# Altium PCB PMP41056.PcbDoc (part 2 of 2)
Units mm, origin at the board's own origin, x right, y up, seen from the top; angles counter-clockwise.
Board outline 20.9 x 34.9 mm, 4 copper layers (Top Layer, Layer 1, Layer 2, Bottom Layer), stack 1.926 mm thick; 24 components, 34 nets, 167 pads, 756 vias.

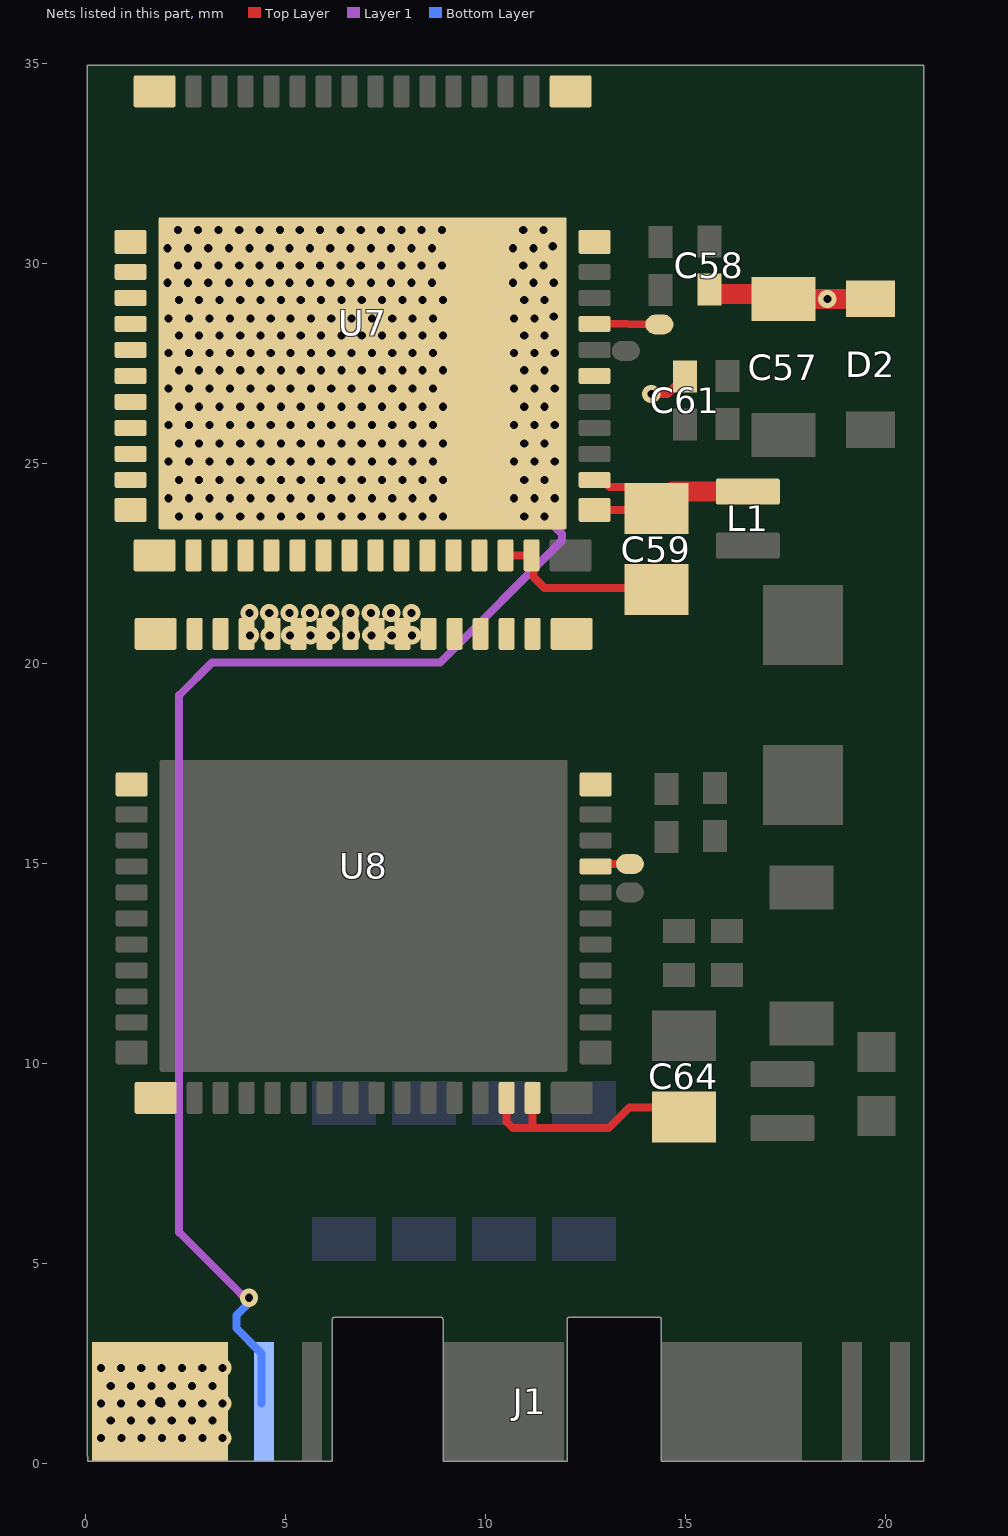
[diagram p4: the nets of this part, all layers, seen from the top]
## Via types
v1: diameter 0.457, hole 0.203, Top Layer to Bottom Layer, tented both sides, 753 vias
v2: diameter 0.5, hole 0.25, Top Layer to Bottom Layer, tented both sides, 3 vias

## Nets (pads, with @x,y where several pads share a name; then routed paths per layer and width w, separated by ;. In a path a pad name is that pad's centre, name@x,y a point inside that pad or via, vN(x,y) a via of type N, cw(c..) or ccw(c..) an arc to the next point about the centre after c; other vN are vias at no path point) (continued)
SW: C57.2 C58.2 C59.2 C61.1 D2.2 J1.8 J1.SW L1.1 U7.18 U7.19 U7.20 U7.21 U7.22 U7.23 U7.24 U7.25 U7.26 U7.27 U7.29 U7.30 U7.31 U7.32 U7.33 U7.34 U7.35 U7.36 U7.37 U7.38 U7.39 U7.40 U7.44 U7.45 U7.49 U7.55 U8.2 U8.3 U8.4 U8.5 U8.6 U8.7 U8.8 U8.9 U8.10 U8.11 U8.12 U8.13 U8.14 U8.15 | length 42.6
  Top Layer w0.2: U7.44@12.73,23.837 C59.2@14.646,23.837 ; U7.45@12.73,24.587 12.93,24.587 13.106,24.411 13.739,24.411 C59.2@14.274,23.876 C59.2@14.695,24.297 ; v1(14.148,26.734) 14.553,26.734 C61.1@14.994,27.175 ; L1.1@16.56,24.297 16.624,24.297 L1.1@16.799,24.472
  Top Layer w0.5: C59.2@14.695,24.297 L1.1@16.56,24.297 ; C58.2@15.599,29.351 15.599,29.279 15.649,29.229 17.327,29.229 C57.2@17.449,29.108 17.451,29.11 v1(18.548,29.11) 19.626,29.11 D2.2@19.628,29.112
  Layer 1 w0.2: v1(4.089,4.14) 4.087,4.14 4.051,4.104 3.928,4.227 3.895,4.227 2.345,5.777 2.345,19.205 3.165,20.026 8.87,20.026 11.916,23.071 11.916,23.237 v1(11.48,23.673)
  Bottom Layer w0.2: v1(4.089,4.14) 4.089,4.077 4.12,4.047 3.775,3.702 3.775,3.38 4.405,2.75 J1.8@4.405,1.5
  other v1: 0.394,0.636 0.899,0.636 1.405,0.636 1.911,0.636 2.417,0.636 2.923,0.636 3.429,0.636 0.635,1.068 1.143,1.068 1.651,1.068 2.159,1.068 2.667,1.068 3.175,1.068 0.394,1.5 0.889,1.5 1.397,1.5 1.905,1.5 2.413,1.5 2.921,1.5 3.429,1.5 0.635,1.932 1.143,1.932 1.651,1.932 2.159,1.932 2.667,1.932 3.175,1.932 0.394,2.389 0.889,2.389 1.397,2.389 1.905,2.389 2.413,2.389 2.921,2.389 3.429,2.389 4.114,20.701 4.609,20.701 5.117,20.701 5.625,20.701 6.133,20.701 6.641,20.701 7.149,20.701 7.657,20.701 8.165,20.701 4.101,21.262 4.596,21.262 5.104,21.262 5.612,21.262 6.12,21.262 6.628,21.262 7.136,21.262 7.644,21.262 8.152,21.262 2.336,23.673 2.844,23.673 3.352,23.673 3.873,23.673 4.381,23.673 4.889,23.673 5.384,23.673 5.892,23.673 6.4,23.673 6.908,23.673 7.416,23.673 7.924,23.673 8.432,23.673 8.94,23.673 10.972,23.673 2.082,24.13 2.59,24.13 3.098,24.13 3.619,24.13 4.127,24.13 4.635,24.13 5.13,24.13 5.638,24.13 6.146,24.13 6.654,24.13 7.162,24.13 7.67,24.13 8.178,24.13 8.686,24.13 10.718,24.13 11.226,24.13 11.734,24.13 2.336,24.587 2.844,24.587 3.352,24.587 3.873,24.587 4.381,24.587 4.889,24.587 5.384,24.587 5.892,24.587 6.4,24.587 6.908,24.587 7.416,24.587 7.924,24.587 8.432,24.587 8.94,24.587 10.972,24.587 11.48,24.587 2.082,25.044 2.59,25.044 3.098,25.044 3.619,25.044 4.127,25.044 4.635,25.044 5.13,25.044 5.638,25.044 6.146,25.044 6.654,25.044 7.162,25.044 7.67,25.044 8.178,25.044 8.686,25.044 10.718,25.044 11.226,25.044 11.734,25.044 2.336,25.502 2.844,25.502 3.352,25.502 3.873,25.502 4.381,25.502 4.889,25.502 5.384,25.502 5.892,25.502 6.4,25.502 6.908,25.502 7.416,25.502 7.924,25.502 8.432,25.502 8.94,25.502 10.972,25.502 11.48,25.502 2.082,25.959 2.59,25.959 3.098,25.959 3.619,25.959 4.127,25.959 4.635,25.959 5.13,25.959 5.638,25.959 6.146,25.959 6.654,25.959 7.162,25.959 7.67,25.959 8.178,25.959 8.686,25.959 10.718,25.959 11.226,25.959 11.734,25.959 2.336,26.416 2.844,26.416 3.352,26.416 3.873,26.416 4.381,26.416 4.889,26.416 5.384,26.416 5.892,26.416 6.4,26.416 6.908,26.416 7.416,26.416 7.924,26.416 8.432,26.416 8.94,26.416 10.972,26.416 11.48,26.416 2.082,26.873 2.59,26.873 3.098,26.873 3.619,26.873 4.127,26.873 4.635,26.873 5.13,26.873 5.638,26.873 6.146,26.873 6.654,26.873 7.162,26.873 7.67,26.873 8.178,26.873 8.686,26.873 10.718,26.873 11.226,26.873 11.734,26.873 2.336,27.33 2.844,27.33 3.352,27.33 3.873,27.33 4.381,27.33 4.889,27.33 5.384,27.33 5.892,27.33 6.4,27.33 6.908,27.33 7.416,27.33 7.924,27.33 8.432,27.33 8.94,27.33 10.972,27.33 11.48,27.33 2.082,27.762 2.59,27.762 3.098,27.762 3.619,27.762 4.127,27.762 4.635,27.762 5.13,27.762 5.638,27.762 6.146,27.762 6.654,27.762 7.162,27.762 7.67,27.762 8.178,27.762 8.686,27.762 10.718,27.762 11.226,27.762 11.734,27.762 2.336,28.194 2.844,28.194 3.352,28.194 3.873,28.194 4.381,28.194 4.889,28.194 5.384,28.194 5.892,28.194 6.4,28.194 6.908,28.194 7.416,28.194 7.924,28.194 8.432,28.194 8.94,28.194 10.972,28.194 11.48,28.194 2.082,28.626 2.59,28.626 3.098,28.626 3.619,28.626 4.127,28.626 4.635,28.626 5.13,28.626 5.638,28.626 6.146,28.626 6.654,28.626 7.162,28.626 7.67,28.626 8.178,28.626 8.686,28.626 10.718,28.626 11.226,28.626 11.708,28.677 2.336,29.083 2.844,29.083 3.352,29.083 3.873,29.083 4.381,29.083 4.889,29.083 5.384,29.083 5.892,29.083 6.4,29.083 6.908,29.083 7.416,29.083 7.924,29.083 8.432,29.083 8.94,29.083 10.972,29.083 11.48,29.083 2.056,29.515 2.564,29.515 3.072,29.515 3.593,29.515 4.101,29.515 4.609,29.515 5.104,29.515 5.612,29.515 6.12,29.515 6.628,29.515 7.136,29.515 7.644,29.515 8.152,29.515 8.66,29.515 10.692,29.515 11.2,29.515 11.708,29.515 2.31,29.947 2.818,29.947 3.326,29.947 3.847,29.947 4.355,29.947 4.863,29.947 5.358,29.947 5.866,29.947 6.374,29.947 6.882,29.947 7.39,29.947 7.898,29.947 8.406,29.947 8.914,29.947 10.946,29.947 11.454,29.947 2.056,30.378 2.564,30.378 3.072,30.378 3.593,30.378 4.101,30.378 4.609,30.378 5.104,30.378 5.612,30.378 6.12,30.378 6.628,30.378 7.136,30.378 7.644,30.378 8.152,30.378 8.66,30.378 10.692,30.378 11.2,30.378 11.683,30.429 2.31,30.836 2.818,30.836 3.326,30.836 3.847,30.836 4.355,30.836 4.863,30.836 5.358,30.836 5.866,30.836 6.374,30.836 6.882,30.836 7.39,30.836 7.898,30.836 8.406,30.836 8.914,30.836 10.946,30.836 11.454,30.836
  other v2: 1.864,1.537
TEMP_H: pad.5@14.35,28.473 U7.51 | length 1.6
  Top Layer w0.2: U7.51@12.773,28.487 12.785,28.499 pad.5@14.35,28.473
TEMP_L: pad.5@13.614,14.986 U8.51 | length 0.9
  Top Layer w0.2: U8.51@12.757,14.924 12.819,14.986 pad.5@13.614,14.986
U1NC1: U7.1
U1NC16: U7.16
U1NC17: U7.17
U1NC28: U7.28
U1NC54: U7.54
U2NC1: U8.1
U2NC16: U8.16
U2NC17: U8.17
U2NC28: U8.28
U2NC54: U8.54
VNEG_H: C59.1 U7.41 U7.42 | length 5.1
  Top Layer w0.2: U7.41@10.505,22.702 U7.42@11.155,22.702 11.205,22.652 11.205,22.157 11.476,21.886 C59.1@14.819,21.886 ; C59.1@14.565,21.886 C59.1@14.646,21.805
VNEG_L: C64.1 U8.41 U8.42 | length 6.1
  Top Layer w0.2: U8.41@10.532,9.139 10.532,8.541 10.692,8.38 11.182,8.38 ; U8.42@11.182,9.139 11.182,8.38 ; C64.1@14.95,8.902 13.6,8.902 13.078,8.38 11.182,8.38

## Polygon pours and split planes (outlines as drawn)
HVBUS on Layer 2 "LAYER_2_HVBUS_P024" (solid, remove dead copper, pour order 24): 1.47,34.925 15.293,34.925 17.195,33.023 17.195,7.747 14.02,4.572 6.514,4.572 5.664,5.422 5.664,7.28 8.127,7.293 9.334,8.5 9.334,30.903 8.106,32.131 2.892,32.131 1.47,33.553
PGND on Layer 2 "LAYER_2_PGND_P043" (solid, remove dead copper, pour order 43): 19.221,0 19.221,6.523 19.221,7.21 18.683,7.747 17.734,7.747 14.509,4.522 14.509,0
SW on Layer 2 "LAYER_2_SW_P025" (solid, remove dead copper, pour order 25): 9.324,31.109 9.324,22.782 8.767,22.225 8.767,20.299 8.66,20.193 4.863,20.193 3.545,18.875 3.545,4.053 4.005,3.594 4.005,0 0.05,0 0.05,30.076 1.13,31.156 9.276,31.156
PGND on Layer 2 "LAYER_2_PGND_P028" (solid, remove dead copper, pour order 28): 12.187,17.719 12.216,13.513 10.359,13.513 10.359,17.535 10.543,17.719
SW on Layer 2 "LAYER_2_SW_P039" (solid, remove dead copper, pour order 39): 12.162,23.444 12.162,30.707 11.55,31.318 10.85,31.318 10.464,30.932 10.464,23.779 10.76,23.483
PGND on Layer 2 "LAYER_2_PGND_P027" (solid, remove dead copper, pour order 27): 12.242,9.797 12.214,13.772 10.359,13.772 10.359,10.081 10.643,9.797
PGND on Layer 2 "LAYER_2_PGND_P026" (solid, remove dead copper, pour order 26): 9.268,17.642 3.897,17.642 3.873,17.618 3.873,8.289 8.936,8.289 9.249,8.602
HVBUS on Layer 1 "LAYER_1_HVBUS_P034" (solid, remove dead copper, pour order 34): 12.347,0.204 12.347,2.569 13.512,3.734 13.512,6.35 5.664,6.35 5.664,5.422 6.514,4.572 6.896,4.572 8.432,3.036 8.432,0.219 8.447,0.204
PGND on Layer 1 "LAYER_1_PGND_P042" (solid, remove dead copper, pour order 42): 20.812,17.907 10.731,17.907 10.359,17.535 10.359,10.053 10.799,9.613 18.826,9.613 20.812,11.599
SW on Layer 1 "LAYER_1_SW_P030" (solid, remove dead copper, pour order 30): 20.097,23.247 10.311,23.247 10.311,31.397 20.097,31.397
PGND on Layer 1 "Layer 1-PGND" (solid, remove dead copper, pour order 37): 19.376,5.612 19.376,9.086 19.065,9.397 10.687,9.397 10.58,9.441 10.102,9.919 10.058,10.026 10.058,17.907 4.378,17.907 3.926,17.455 3.926,8.515 5.243,7.198 13.966,7.198 14.782,6.382 14.782,0 18.505,0 19.065,0.56 19.065,5.301
SW on Layer 1 "LAYER_1_SW_P029" (solid, remove dead copper, pour order 29): 2.91,20.193 9.956,20.193 9.956,31.397 1.371,31.398 0.204,30.23 0.204,0 4.005,0 4.005,3.881 2.027,5.858 2.027,19.31
HVBUS on Layer 1 "LAYER_1_HVBUS_P040" (solid, remove dead copper, pour order 40): 0.659,32.131 17.195,32.131 17.195,34.925 0.659,35
HVBUS on Bottom Layer "BOTTOM_LAYER_HVBUS_P023" (solid, remove dead copper, pour order 23): 13.504,0 8.556,0 8.556,3.074 5.664,5.966 5.664,6.35 13.504,6.35
PGND on Bottom Layer "Top Layer-PGND" (solid, remove dead copper, pour order 36): 20.655,7.01 19.699,7.01 18.576,5.887 18.576,0.914 18.297,0.635 14.909,0.635 14.782,0.762 14.782,7.198 13.576,8.404 0.638,8.404 0.204,8.838 0.204,17.719 0.392,17.907 10.356,17.907 20.655,17.907
SW on Bottom Layer "BOTTOM_LAYER_SW_P033" (solid, remove dead copper, pour order 33): 0.832,31.318 19.044,31.318 20.097,30.265 20.097,21.862 17.789,19.553 1.113,19.553 0.204,20.463 0.204,30.69
HVBUS on Bottom Layer "BOTTOM_LAYER_HVBUS_P041" (solid, remove dead copper, pour order 41): 0.891,33.147 17.195,33.147 17.195,34.925 0.862,34.925
HVBUS on Top Layer "TOP_LAYER_HVBUS_P038" (solid, remove dead copper, pour order 38): 11.963,0.204 11.963,2.651 13.512,4.199 13.512,5.966 13.128,6.35 5.664,6.35 5.664,5.706 6.798,4.572 8.763,2.607 8.763,0.204
PGND on Top Layer "TOP_LAYER_PGND_P035" (solid, remove dead copper, pour order 35): 12.807,8.315 12.807,17.907 0.392,17.907 0.204,17.719 0.204,8.637 0.526,8.315
SW on Top Layer "TOP_LAYER_SW_P031" (solid, remove dead copper, pour order 31): 12.91,31.398 1.723,31.398 0.59,30.265 0.59,21.914 2.31,20.193 12.91,20.193
HVBUS on Top Layer "TOP_LAYER_HVBUS_P032" (solid, remove dead copper, pour order 32): 2.194,33.147 17.195,33.147 17.195,34.925 2.164,34.925

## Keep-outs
Keep-Out Layer:
  text ".Layer_Name" at 41.348,-59.464 h1.52

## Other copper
Top Layer:
  region net PGND: 18.429,6.401 14.86,6.401 14.86,0.254 18.429,0.254
  text ".Layer_Name" at 41.348,-59.464 h1.52
Bottom Layer:
  text ".Layer_Name" at 41.348,-59.464 h1.52

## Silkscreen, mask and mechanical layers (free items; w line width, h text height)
Top Overlay:
  text ".Layer_Name" at 41.348,-59.464 h1.52
Bottom Overlay:
  text "'.PRJ_Number'.PCB_Rev" at -95.734,-34.38 h2.75
  text ".Layer_Name" at 41.348,-59.464 h1.52
Top Paste:
  text ".Layer_Name" at 41.348,-59.464 h1.52
Bottom Paste:
  region: 8.94,30.988 5.94,30.988 5.94,27.988 8.94,27.988
  region: 5.257,30.988 2.257,30.988 2.257,27.988 5.257,27.988
  region: 8.94,24.257 8.94,27.257 5.94,27.257 5.94,24.257
  region: 5.257,24.257 5.257,27.257 2.257,27.257 2.257,24.257
  region: 8.94,20.749 8.94,23.749 5.94,23.749 5.94,20.749
  region: 5.257,20.749 5.257,23.749 2.257,23.749 2.257,20.749
  region: 13.893,20.749 13.893,23.749 10.893,23.749 10.893,20.749
  region: 17.576,20.749 17.576,23.749 14.576,23.749 14.576,20.749
  region: 13.893,24.257 13.893,27.257 10.893,27.257 10.893,24.257
  region: 17.576,24.257 17.576,27.257 14.576,27.257 14.576,24.257
  region: 13.893,30.988 10.893,30.988 10.893,27.988 13.893,27.988
  region: 17.576,30.988 14.576,30.988 14.576,27.988 17.576,27.988
  rectangle: 1.876,14.224 4.876,17.224
  rectangle: 1.876,10.541 4.876,13.541
  rectangle: 5.384,14.224 8.384,17.224
  rectangle: 5.384,10.541 8.384,13.541
  region: 12.115,14.224 12.115,17.224 9.115,17.224 9.115,14.224
  region: 12.115,10.541 12.115,13.541 9.115,13.541 9.115,10.541
  text ".Layer_Name" at 41.348,-59.464 h1.52
Top Solder:
  text ".Layer_Name" at 41.348,-59.464 h1.52
Bottom Solder:
  region: 18.49,9.891 18.49,17.891 13.081,17.891 13.081,9.891
  region: 12.496,9.919 12.496,17.919 1.496,17.919 1.496,9.919
  region: 18.177,31.385 10.177,31.385 10.177,20.385 18.177,20.385
  region: 9.451,31.318 1.451,31.318 1.451,20.318 9.451,20.318
  text ".Layer_Name" at 41.348,-59.464 h1.52
  text ".Layer_Name" at 41.348,-59.464 h1.52
Drill Guide:
  text ".Layer_Name" at 41.348,-59.464 h1.52
M1 Board Outline:
  lines w0.1: 0,0 0,35 ; 0.005,0.165 0.005,0 6.223,0 6.223,3.6 8.89,3.6 8.89,0 12.09,0 12.09,3.6 14.351,3.6 14.351,0 21.005,0 21.005,35 ; 0,35 ccw(c0,35) 0,35 ; 0,35 21.005,35 ; 21.005,35 ccw(c21.005,35) 21.005,35 ; 21.005,35 21.005,35
  text "hole in PAD" at 23.292,1.168 h1.52 r90
  text ".Layer_Name" at 41.348,-59.464 h1.52
M2 Board Dimensions:
  region: 56.004,-41.468 52.829,-41.468 52.829,-44.643 56.004,-44.643
  region: 52.829,-44.643 43.304,-44.643 43.304,-47.818 52.829,-47.818
  lines w0.178: 30.604,-44.643 56.004,-44.643 ; 36.954,-47.818 36.954,-41.468 ; 43.304,-47.818 43.304,-41.468 ; 49.654,-47.818 49.654,-41.468 ; 52.829,-47.818 52.829,-41.468 ; 30.604,-47.818 56.004,-47.818 56.004,-41.468 30.604,-41.468 30.604,-47.818
  text ".Layer_Name" at 41.348,-59.464 h1.52
M3 3D STEP Top:
  text ".Layer_Name" at 41.348,-59.464 h1.52
M4 3D STEP Bottom:
  text ".Layer_Name" at 41.348,-59.464 h1.52
M5 Assembly Top:
  lines w0.254: -104.257,-61.297 63.383,-61.297 ; -104.257,-56.133 63.434,-56.133 ; -104.257,-50.968 -104.257,-66.462 -2.53,-66.462 63.434,-66.462 63.434,-50.968 -104.245,-50.968 -104.245,-66.462 -64.227,-66.462 ; -41.646,-66.462 -41.646,-50.968 ; -9.464,-56.133 -9.464,-50.968 ; 11.872,-56.133 11.872,-50.968 ; 27.67,-66.627 27.67,-61.475
  text "COMPONENTS MARKED 'DNP' SHOULD NOT BE POPULATED." at -98.987,-45.736 h1.52
  text "ASSEMBLY VARIANT:" at -98.86,-48.682 h1.52
  text ".VariantName" at -72.469,-48.682 h1.52
  text "PCB VIEWED FROM BOTTOM SIDE" at -102.644,-54.325 h1.52
  text "BOARD #:" at -39.741,-54.325 h1.52
  text ".PRJ_Number" at -25.886,-54.325 h1.52
  text "REV:" at -4.435,-54.325 h1.52
  text ".PCB_Rev" at 2.969,-54.325 h1.52
  text "SVN REV:" at 16.85,-54.325 h1.52
  text ".VersionControl_RevNumber" at 29.702,-54.325 h1.52
  text "TID #:" at -39.741,-59.49 h1.52
  text ".TID" at -25.886,-59.49 h1.52
  text "PLOT NAME =" at -102.644,-64.705 h1.52
  text ".plot_File_Name" at -82.185,-64.705 h1.52
  text "GENERATED    :" at -39.69,-64.705 h1.52
  text ".Print_Date" at -17.605,-64.705 h1.52
  text ".Print_Time" at 0.911,-64.705 h1.52
  text "TEXAS INSTRUMENTS" at 33.03,-64.705 h1.52
M6 Assembly Bottom:
  lines w0.254: -104.27,-56.12 63.421,-56.12 ; -104.219,-61.285 63.421,-61.285 ; -68.507,-66.614 -68.507,-61.463 ; -52.708,-56.12 -52.708,-50.955 ; -31.372,-56.12 -31.372,-50.955 ; 0.81,-66.449 0.81,-50.955 ; 23.39,-66.449 63.408,-66.449 63.408,-50.955 -104.27,-50.955 -104.27,-66.449 -38.306,-66.449 63.421,-66.449 63.421,-50.955
  text "COMPONENTS MARKED 'DNP' SHOULD NOT BE POPULATED." at 26.705,-45.748 h1.52
  text ".VariantName" at 0.403,-48.682 h1.52
  text "ASSEMBLY VARIANT:" at 26.718,-48.682 h1.52
  text ".VersionControl_RevNumber" at -70.539,-54.312 h1.52
  text "SVN REV:" at -57.686,-54.312 h1.52
  text ".PCB_Rev" at -43.805,-54.312 h1.52
  text "REV:" at -36.401,-54.312 h1.52
  text ".PRJ_Number" at -14.951,-54.312 h1.52
  text "BOARD #:" at -1.095,-54.312 h1.52
  text "PCB VIEWED FROM TOP SIDE" at 61.808,-54.312 h1.52
  text ".TID" at -14.951,-59.477 h1.52
  text "TID #:" at -1.095,-59.477 h1.52
  text "TEXAS INSTRUMENTS" at -73.866,-64.693 h1.52
  text ".Print_Time" at -41.748,-64.693 h1.52
  text ".Print_Date" at -23.231,-64.693 h1.52
  text "GENERATED    :" at -1.146,-64.693 h1.52
  text ".plot_File_Name" at 41.348,-64.693 h1.52
  text "PLOT NAME =" at 61.808,-64.693 h1.52
M9 Title Sheet:
  drawing of 57 lines, arcs and shapes, not listed
  text "1" at -16.207,166.469 h1.78
  text "2" at 47.183,166.469 h1.78
  text "3" at 110.412,166.469 h1.78
  text "4" at 174.081,166.469 h1.78
  text "5" at 237.556,166.469 h1.78
  text "6" at 301.183,166.469 h1.78
  text "A" at -45.578,137.436 h1.78
  text "A" at 330.342,137.436 h1.78
  text "B" at -45.578,76.984 h1.78
  text "B" at 330.342,76.984 h1.78
  text "C" at -45.578,16.659 h1.78
  text "C" at 330.342,16.659 h1.78
  text "PROJECT TITLE:" at 253.126,-30.61 h1.14
  text ".PRJ_Title" at 254.396,-33.996 h1.78
  text "DESIGNED FOR:" at 253.126,-38.255 h1.14
  text ".PRJ_Customer" at 254.396,-41.811 h1.78
  text "D" at -45.578,-43.539 h1.78
  text "D" at 330.342,-43.539 h1.78
  text "FILE NAME:" at 253.126,-45.875 h1.14
  text ".PCB_File_Name_No_Path" at 254.396,-48.923 h1.78
  text "Texas Instruments (TI) and/or its licensors do not warrant the accuracy or completeness of this specification" at 126.9,-53.034 h1.14
  text "ENGINEER:" at 253.126,-53.241 h1.14
  text "LAYOUT BY:" at 291.353,-53.241 h1.14
  text "or any information contained therein. TI and/or its licensors do not warrant that this design will meet" at 125.758,-55.896 h1.14
  text ".PRJ_Engineer" at 254.396,-57.178 h1.78
  text ".PCB_Layout" at 292.635,-57.178 h1.78
  text "the specifications, will be suitable for your application or fit for any particular purpose, or will operate in" at 125.758,-58.757 h1.14
  text ".Layer_Name" at -20.343,-59.464 h1.52
  text "ALTIUM DESIGNER VERSION:" at 291.353,-61.115 h1.14
  text "an implementation. TI and/or its licensors do not warrant that the design is production worthy. You should" at 125.758,-61.619 h1.14
  text "completely validate and test your design implementation to confirm the system functionality for your application." at 126.9,-64.481 h1.14
  text ".print_Scale" at 254.396,-64.502 h1.78
  text ".Application_BuildNumber" at 292.635,-64.502 h1.78
  text "1" at -16.207,-69.751 h1.78
  text "2" at 47.183,-69.751 h1.78
  text "3" at 110.412,-69.751 h1.78
  text "4" at 174.081,-69.751 h1.78
  text "5" at 237.556,-69.751 h1.78
  text "6" at 301.183,-69.751 h1.78
M10 Fab Notes:
  drawing of 189 lines, arcs and shapes, not listed
  text "DESIGN INFORMATION" at -258.499,123.788 h1.52
  text "MIL" at -273.903,120.432 h1.52
  text "8" at -269.972,120.432 h1.52
  text "MIN. TRACK WIDTH:" at -242.127,120.432 h1.52
  text "7.874" at -265.746,117.342 h1.52
  text "MIL" at -273.903,117.28 h1.52
  text "MIN. CLEARANCE:" at -242.127,117.28 h1.52
  text "MIL" at -273.903,114.127 h1.52
  text "24" at -269.21,114.127 h1.52
  text "MIN. VIA PAD SIZE:" at -242.127,114.127 h1.52
  text "0.05mm (2MIL)" at -259.78,110.827 h1.52
  text "EXTERNAL" at -277.764,110.618 h1.52
  text "MINIMUM ANNULAR RING" at -233.765,110.618 h1.52
  text "IPC-D-275 CLASS 2 LEVEL C" at -244.433,107.821 h1.52
  text "PER" at -238.845,107.821 h1.52
  text "MIL, HOLES" at -282.234,105.269 h1.52
  text "+/-" at -293.957,105.051 h1.52
  text "+/-" at -272.266,105.051 h1.52
  text "MIL" at -302.986,105.024 h1.52
  text "3" at -300.033,105.024 h1.52
  text "5" at -278.875,105.024 h1.52
  text "METAL" at -264.239,105.024 h1.52
  text "REGISTRATION TOLERANCES:" at -233.765,105.024 h1.52
  text "HOLE SIZE TOLERANCE (UNLESS OTHERWISE SPECIFIED):" at -233.765,102.527 h1.52
  text "+/-" at -293.957,102.454 h1.52
  text "MIL" at -302.986,102.427 h1.52
  text "3" at -300.033,102.427 h1.52
  text "MATERIAL:" at -231.866,98.931 h1.52
  text "FR-4 High Tg" at -256.922,95.666 h1.52
  text "X" at -253.253,95.463 h1.52
  text "OTHER" at -280.354,95.348 h1.52
  text "FR-408" at -242.559,95.348 h1.52
  text "62 MIL (1.6mm) +/-10%" at -250.69,91.715 h1.52
  text "X" at -247.639,91.653 h1.52
  text "OTHER" at -283.326,91.507 h1.52
  text "THICKNESS:" at -233.765,91.507 h1.52
  text "ANSI IPC-6012 TYPE 3 CLASS 2" at -259.832,87.993 h1.52
  text "X" at -255.31,87.993 h1.52
  text "TOLERANCE:" at -233.765,87.993 h1.52
  text "OTHER +/-" at -259.831,84.331 h1.52
  text "ANSI IPC-6012 TYPE 3 CLASS 2" at -259.832,80.643 h1.52
  text "X" at -255.31,80.643 h1.52
  text "BOW & TWIST:" at -233.765,80.643 h1.52
  text "OTHER +/-" at -259.831,76.917 h1.52
  text "DRILLING:" at -231.866,73.599 h1.52
  text "NC_DRILL FILES" at -276.595,70.928 h1.52
  text "X" at -273.344,70.828 h1.52
  text "AS SHOWN" at -254.98,70.828 h1.52
  text "X" at -250.459,70.825 h1.52
  text "REFERENCE:" at -233.765,70.828 h1.52
  text "OTHER" at -284.164,67.214 h1.52
  text "20-30 um" at -265.944,67.125 h1.52
  text "X" at -262.693,67.125 h1.52
  text "PTH COPPER THICKNESS:" at -233.757,67.125 h1.52
  text "BOARD FINISH:" at -231.866,63.376 h1.52
  text "BOTTOM" at -276.087,60.579 h1.52
  text "X" at -273.09,60.579 h1.52
  text "TOP" at -263.108,60.579 h1.52
  text "X" at -260.136,60.579 h1.52
  text "SILKSCREEN:" at -235.808,60.579 h1.52
  text "OTHER" at -276.087,56.637 h1.52
  text "WHITE" at -263.108,56.637 h1.52
  text "X" at -260.111,56.637 h1.52
  text "SILKSCREEN COLOR:" at -235.808,56.637 h1.52
  text "OTHER" at -282.132,52.993 h1.52
  text "GREEN" at -266.435,52.993 h1.52
  text "X" at -263.438,52.993 h1.52
  text "SOLDER RESIST COLOR:" at -235.808,52.819 h1.52
  text "MATTE" at -266.435,49.075 h1.52
  text "X" at -263.438,49.075 h1.52
  text "SEMI-GLOSS" at -282.121,49.059 h1.52
  text "IMMERSION GOLD (ENIG)" at -258.815,44.687 h1.52
  text "ENEPIG" at -292.789,44.503 h1.52
  text "X" at -254.294,44.478 h1.52
  text "SURFACE FINISH:" at -231.866,44.478 h1.52
  text "IMM. TIN/SILVER OR EQUIV" at -240.236,40.99 h1.52
  text "OTHER" at -276.595,40.89 h1.52
  text "ARRAY/PANEL:" at -231.866,36.944 h1.52
  text "CUT AND TRIM PER M1 BOARD OUTLINE" at -258.815,36.735 h1.52
  text "V. SCORE" at -280.812,33.281 h1.52
  text "X" at -276.291,33.281 h1.52
  text "N.C. ROUTE" at -258.815,33.281 h1.52
  text "MATERIALS AND WORKMANSHIP FOR ALL PCBS" at -250.281,30.001 h1.52
  text "CERTIFICATION:" at -231.866,30.001 h1.52
  text "TO MEET OR EXCEED THE REQUIREMENTS OF:" at -250.281,27.612 h1.52
  text "2" at -288.978,24.345 h1.52
  text "X" at -286.184,24.345 h1.52
  text "ANSI IPC-A-600F CLASS ->" at -244.325,24.345 h1.52
  text "X" at -241.074,24.345 h1.52
  text "3" at -297.969,24.307 h1.52
  text "1" at -280.977,24.307 h1.52
  text "PER ORDER" at -291.403,20.594 h1.52
  text "OTHER" at -281.317,20.594 h1.52
  text "RoHS" at -264.949,20.594 h1.52
  text "X" at -261.698,20.594 h1.52
  text "ALL BOARDS MUST MEET OR EXCEED UL94-V0 REQUIREMENTS." at -232.565,16.687 h1.52
  text "PCB MUST BEAR THE UL94V-0 UL REGISTERED MATERIAL ID NUMBER" at -232.565,13.739 h1.52
  text "ADDITIONAL REQUIREMENTS:" at -231.866,9.435 h1.52
  text "YES" at -256.771,6.714 h1.52
  text "MICROSECTION:" at -233.765,6.714 h1.52
  text "REQUIRED" at -278.653,3.048 h1.52
  text "PER ORDER" at -293.689,2.976 h1.52
  text "X" at -275.656,2.976 h1.52
  text "NONE" at -266.931,2.976 h1.52
  text "BARE BOARD ELEC. TEST:" at -233.765,2.976 h1.52
  text "XX MIL VIAS REQUIRE NON-CONDUCTIVE FILL AND PLANARIZE" at -238.036,-2.23 h1.5
  text "XX MIL VIAS REQUIRE CONDUCTIVE FILL AND PLANARIZE" at -238.239,-4.871 h1.52
  text "OUTER XX MIL TRACES REQUIRE 50 OHM SINGLE-ENDED IMPEDANCE" at -238.214,-9.021 h1.47
  text "LAYER 2 & 3 (INNER LAYERS) XX MIL WIDE, XX MIL SPACE / TRACES REQUIRE 100 OHM DIFFERENTIAL IMPEDANCE" at -238.011,-15.008 h1.52
  text ".Layer_Name" at 41.348,-59.464 h1.52
M11 Gerber Information:
  lines w0.254: -104.27,-56.12 63.421,-56.12 ; -104.219,-61.285 63.421,-61.285 ; -68.507,-66.614 -68.507,-61.463 ; -52.708,-56.12 -52.708,-50.955 ; -31.372,-56.12 -31.372,-50.955 ; 0.81,-66.449 0.81,-50.955 ; 23.39,-66.449 63.408,-66.449 63.408,-50.955 -104.27,-50.955 -104.27,-66.449 -38.306,-66.449 63.421,-66.449 63.421,-50.955
  text ".VersionControl_RevNumber" at -70.539,-54.312 h1.52
  text "SVN REV:" at -57.686,-54.312 h1.52
  text ".PCB_Rev" at -43.805,-54.312 h1.52
  text "REV:" at -36.401,-54.312 h1.52
  text ".PRJ_Number" at -14.951,-54.312 h1.52
  text "BOARD #:" at -1.095,-54.312 h1.52
  text "ALL ARTWORK VIEWED FROM TOP SIDE" at 61.808,-54.312 h1.52
  text "LAYER NAME =" at 61.808,-59.464 h1.52
  text ".TID" at -14.951,-59.477 h1.52
  text "TID #:" at -1.095,-59.477 h1.52
  text "TEXAS INSTRUMENTS" at -73.866,-64.693 h1.52
  text ".Print_Time" at -41.748,-64.693 h1.52
  text ".Print_Date" at -23.231,-64.693 h1.52
  text "GENERATED    :" at -1.146,-64.693 h1.52
  text ".plot_File_Name" at 41.348,-64.693 h1.52
  text "PLOT NAME =" at 61.808,-64.693 h1.52
M12 Stackup:
  drawing of 297 lines, arcs and shapes, not listed
  text "Layer" at -167.071,157.793 h1.52
  text "Name" at -156.659,157.793 h1.52
  text "Material" at -133.043,157.793 h1.52
  text "Thickness" at -111.205,157.793 h1.52
  text "Constant" at -94.699,157.793 h1.52
  text "Board Layer Stack" at -80.225,157.793 h1.52
  text "1" at -167.071,154.745 h1.52
  text "Top Overlay" at -156.659,154.745 h1.52
  text "2" at -167.071,151.697 h1.52
  text "Top Solder" at -156.659,151.697 h1.52
  text "Solder Resist" at -133.043,151.697 h1.52
  text "0.40mil" at -111.205,151.697 h1.52
  text "3.5" at -94.699,151.697 h1.52
  text "3" at -167.071,148.649 h1.52
  text "Top Layer" at -156.659,148.649 h1.52
  text "Copper" at -133.043,148.649 h1.52
  text "2.76mil" at -111.205,148.649 h1.52
  text "4" at -167.071,145.601 h1.52
  text "Dielectric 1" at -156.659,145.601 h1.52
  text "PP-006" at -133.043,145.601 h1.52
  text "2.80mil" at -111.205,145.601 h1.52
  text "4.1" at -94.699,145.601 h1.52
  text "5" at -167.071,142.553 h1.52
  text "Layer 1" at -156.659,142.553 h1.52
  text "Copper" at -133.043,142.553 h1.52
  text "2.76mil" at -111.205,142.553 h1.52
  text "6" at -167.071,139.505 h1.52
  text "Dielectric1" at -156.659,139.505 h1.52
  text "FR-4 High Tg" at -133.043,139.505 h1.52
  text "59.20mil" at -111.205,139.505 h1.52
  text "4.8" at -94.699,139.505 h1.52
  text "7" at -167.071,136.457 h1.52
  text "Layer 2" at -156.659,136.457 h1.52
  text "Copper" at -133.043,136.457 h1.52
  text "2.76mil" at -111.205,136.457 h1.52
  text "8" at -167.071,133.409 h1.52
  text "Dielectric 2" at -156.659,133.409 h1.52
  text "PP-006" at -133.043,133.409 h1.52
  text "2.80mil" at -111.205,133.409 h1.52
  text "4.1" at -94.699,133.409 h1.52
  text "9" at -167.071,130.361 h1.52
  text "Bottom Layer" at -156.659,130.361 h1.52
  text "Copper" at -133.043,130.361 h1.52
  text "2.76mil" at -111.205,130.361 h1.52
  text "10" at -167.071,127.313 h1.52
  text "Bottom Solder" at -156.659,127.313 h1.52
  text "Solder Resist" at -133.043,127.313 h1.52
  text "0.40mil" at -111.205,127.313 h1.52
  text "3.5" at -94.699,127.313 h1.52
  text "11" at -167.071,124.265 h1.52
  text "Bottom Overlay" at -156.659,124.265 h1.52
  text ".Layer_Name" at 41.348,-59.464 h1.52
M13 Component Bodies Top:
  text ".Layer_Name" at 41.348,-59.464 h1.52
M14 Component Bodies Bottom:
  text ".Layer_Name" at 41.348,-59.464 h1.52
M15 Courtyards Top:
  text ".Layer_Name" at 41.348,-59.464 h1.52
M16 Courtyards Bottom:
  text ".Layer_Name" at 41.348,-59.464 h1.52
Drill Drawing:
  lines w0.254: -133.797,79.365 -132.393,79.365 -133.095,77.962 -133.797,79.365 ; -133.797,81.821 -133.095,81.12 -132.393,81.821 -133.095,82.523 -133.797,81.821
  lines w0.305: -135.069,77.014 -52.989,77.014 ; -135.069,83.33 -52.989,83.33 ; -126.487,73.857 -126.487,86.488 ; -118.055,73.857 -118.055,86.488 ; -101.886,73.857 -101.886,86.488 ; -95.304,73.857 -95.304,86.488 ; -85.775,73.857 -85.775,86.488 ; -67.377,73.857 -67.377,86.488 ; -135.069,73.857 -52.989,73.857 -52.989,86.488 -135.069,86.488 -135.069,73.857
  text "Symbol" at -133.174,84.277 h1.83
  text "Quantity" at -125.54,84.277 h1.83
  text "Finished Hole Size" at -117.107,84.277 h1.83
  text "Plated" at -100.939,84.277 h1.83
  text "Hole Type" at -94.356,84.277 h1.83
  text "Drill Layer Pair" at -84.827,84.277 h1.83
  text "Hole Tolerance" at -66.429,84.277 h1.83
  text "753" at -125.54,81.12 h1.52
  text "8.00mil (0.203mm)" at -117.107,81.12 h1.52
  text "PTH" at -100.939,81.12 h1.52
  text "Round" at -94.356,81.12 h1.52
  text "Top Layer - Bottom Layer" at -84.827,81.12 h1.52
  text "3" at -125.54,77.962 h1.52
  text "9.84mil (0.250mm)" at -117.107,77.962 h1.52
  text "PTH" at -100.939,77.962 h1.52
  text "Round" at -94.356,77.962 h1.52
  text "Top Layer - Bottom Layer" at -84.827,77.962 h1.52
  text "756 Total" at -125.54,74.804 h1.52
  text ".Layer_Name" at 41.348,-59.464 h1.52
M17 Embedded Cavity:
  text ".Layer_Name" at 41.348,-59.464 h1.52
M18 Embedded Assembly:
  text ".Layer_Name" at 41.348,-59.464 h1.52
M19 Embedded Keepout:
  lines w1.2: -1.855,4.445 13.545,4.445
  text ".Layer_Name" at 41.348,-59.464 h1.52

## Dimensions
14.355,0 to 0,35 on M2 Board Dimensions
21.005,35 to 0,35 on M2 Board Dimensions
56.004,-47.818 to 30.604,-47.818 on M2 Board Dimensions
